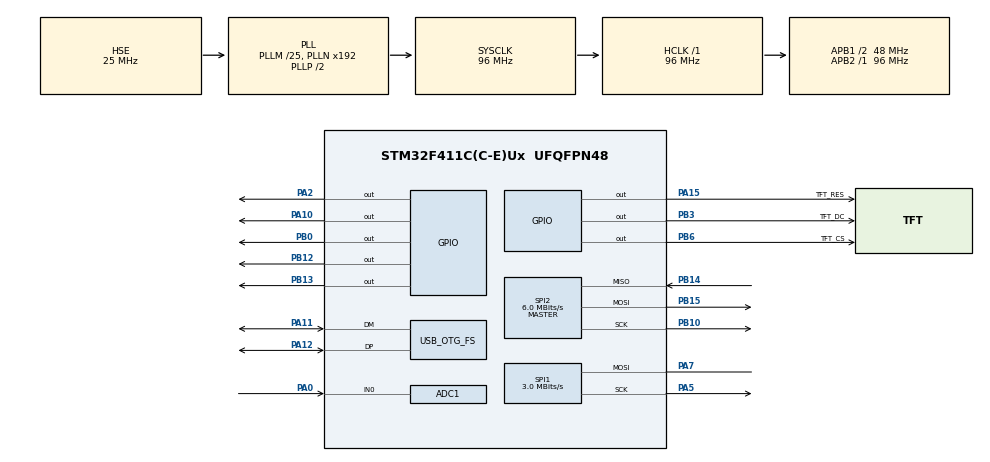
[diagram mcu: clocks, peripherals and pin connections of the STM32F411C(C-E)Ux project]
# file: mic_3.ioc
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ADC1.Channel-2\#ChannelRegularConversion=ADC_CHANNEL_0
ADC1.ClockPrescaler=ADC_CLOCK_SYNC_PCLK_DIV4
ADC1.ExternalTrigConv=ADC_EXTERNALTRIGCONV_T2_TRGO
ADC1.NbrOfConversionFlag=1
ADC1.Rank-2\#ChannelRegularConversion=1
ADC1.SamplingTime-2\#ChannelRegularConversion=ADC_SAMPLETIME_15CYCLES
ADC1.master=1
Dma.ADC1.0.Direction=DMA_PERIPH_TO_MEMORY
Dma.ADC1.0.FIFOMode=DMA_FIFOMODE_DISABLE
Dma.ADC1.0.Instance=DMA2_Stream0
Dma.ADC1.0.MemDataAlignment=DMA_MDATAALIGN_WORD
Dma.ADC1.0.MemInc=DMA_MINC_ENABLE
Dma.ADC1.0.Mode=DMA_CIRCULAR
Dma.ADC1.0.PeriphDataAlignment=DMA_PDATAALIGN_WORD
Dma.ADC1.0.PeriphInc=DMA_PINC_DISABLE
Dma.ADC1.0.Priority=DMA_PRIORITY_LOW
Dma.Request0=ADC1
FATFS._MAX_SS=4096
FATFS._USE_LFN=1
Mcu.Family=STM32F4
Mcu.Name=STM32F411C(C-E)Ux
Mcu.Package=UFQFPN48
NVIC.DMA2_Stream0_IRQn=true\:0\:0\:false\:false\:true\:false\:true\:true
NVIC.OTG_FS_IRQn=true\:0\:0\:false\:false\:true\:false\:true\:true
NVIC.PriorityGroup=NVIC_PRIORITYGROUP_4
PA0-WKUP.Signal=ADCx_IN0
PA10.Signal=GPIO_Output
PA11.Mode=Device_Only
PA11.Signal=USB_OTG_FS_DM
PA12.Mode=Device_Only
PA12.Signal=USB_OTG_FS_DP
PA13.Mode=Serial_Wire
PA13.Signal=SYS_JTMS-SWDIO
PA14.Mode=Serial_Wire
PA14.Signal=SYS_JTCK-SWCLK
PA15.GPIO_Label=TFT_RES
PA15.Signal=GPIO_Output
PA2.Signal=GPIO_Output
PA5.Mode=Simplex_Bidirectional_Master
PA5.Signal=SPI1_SCK
PA7.Mode=Simplex_Bidirectional_Master
PA7.Signal=SPI1_MOSI
PB0.Signal=GPIO_Output
PB10.Mode=Full_Duplex_Master
PB10.Signal=SPI2_SCK
PB12.Signal=GPIO_Output
PB13.Signal=GPIO_Output
PB14.Mode=Full_Duplex_Master
PB14.Signal=SPI2_MISO
PB15.Mode=Full_Duplex_Master
PB15.Signal=SPI2_MOSI
PB3.GPIO_Label=TFT_DC
PB3.Signal=GPIO_Output
PB6.GPIO_Label=TFT_CS
PB6.Signal=GPIO_Output
PH0\ -\ OSC_IN.Mode=HSE-External-Oscillator
PH0\ -\ OSC_IN.Signal=RCC_OSC_IN
PH1\ -\ OSC_OUT.Mode=HSE-External-Oscillator
PH1\ -\ OSC_OUT.Signal=RCC_OSC_OUT
ProjectManager.HeapSize=0x1000
ProjectManager.StackSize=0x400
ProjectManager.TargetToolchain=CMake
RCC.48MHZClocksFreq_Value=48000000
RCC.AHBFreq_Value=96000000
RCC.APB1CLKDivider=RCC_HCLK_DIV2
RCC.APB1Freq_Value=48000000
RCC.APB1TimFreq_Value=96000000
RCC.APB2Freq_Value=96000000
RCC.APB2TimFreq_Value=96000000
RCC.CortexFreq_Value=96000000
RCC.HCLKFreq_Value=96000000
RCC.HSE_VALUE=25000000
RCC.HSI_VALUE=16000000
RCC.LSE_VALUE=32768
RCC.PLLM=25
RCC.SYSCLKFreq_VALUE=96000000
RCC.SYSCLKSource=RCC_SYSCLKSOURCE_PLLCLK
RCC.VCOOutputFreq_Value=192000000
SH.ADCx_IN0.0=ADC1_IN0,IN0
SPI1.BaudRatePrescaler=SPI_BAUDRATEPRESCALER_32
SPI1.CalculateBaudRate=3.0 MBits/s
SPI1.Direction=SPI_DIRECTION_1LINE
SPI1.Mode=SPI_MODE_MASTER
SPI1.VirtualType=VM_MASTER
SPI2.BaudRatePrescaler=SPI_BAUDRATEPRESCALER_8
SPI2.CalculateBaudRate=6.0 MBits/s
SPI2.Direction=SPI_DIRECTION_2LINES
SPI2.Mode=SPI_MODE_MASTER
SPI2.VirtualType=VM_MASTER
TIM2.Period=8000-1
TIM2.Prescaler=1-1
TIM2.TIM_MasterOutputTrigger=TIM_TRGO_UPDATE
TIM2.TIM_MasterSlaveMode=TIM_MASTERSLAVEMODE_ENABLE
USB_DEVICE.CLASS_NAME_FS=CDC
USB_DEVICE.VirtualMode=Cdc
USB_DEVICE.VirtualModeFS=Cdc_FS
USB_OTG_FS.VirtualMode=Device_Only
VP_FATFS_VS_Generic.Mode=User_defined
VP_TIM2_VS_ClockSourceINT.Mode=Internal
VP_USB_DEVICE_VS_USB_DEVICE_CDC_FS.Mode=CDC_FS
board=custom

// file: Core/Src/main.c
/* USER CODE BEGIN Header */
/**
  ******************************************************************************
  * @file           : main.c
  * @brief          : Main program body
  ******************************************************************************
  */
/* USER CODE END Header */
#include "main.h"
#include "fatfs.h"
#include "usb_device.h"

/* USER CODE BEGIN Includes */
#include "app.h"
#include "board.h"
/* USER CODE END Includes */

ADC_HandleTypeDef hadc1;
DMA_HandleTypeDef hdma_adc1;

SPI_HandleTypeDef hspi1;
SPI_HandleTypeDef hspi2;

TIM_HandleTypeDef htim2;

void SystemClock_Config(void);
static void MX_GPIO_Init(void);
static void MX_DMA_Init(void);
static void MX_ADC1_Init(void);
static void MX_TIM2_Init(void);
static void MX_SPI1_Init(void);
static void MX_SPI2_Init(void);

int main(void)
{

  /* MCU Configuration--------------------------------------------------------*/

  /* Reset of all peripherals, Initializes the Flash interface and the Systick. */
  HAL_Init();

  /* Configure the system clock */
  SystemClock_Config();

  /* Initialize all configured peripherals */
  MX_GPIO_Init();
  MX_DMA_Init();
  MX_ADC1_Init();
  MX_USB_DEVICE_Init();
  MX_TIM2_Init();
  MX_SPI1_Init();
  MX_SPI2_Init();
  MX_FATFS_Init();
  /* USER CODE BEGIN 2 */
  App_Init();
  /* USER CODE END 2 */

  /* Infinite loop */
  /* USER CODE BEGIN WHILE */
  while (1)
  {
    App_Run();
    /* USER CODE END WHILE */

  }
}

void SystemClock_Config(void)
{
  RCC_OscInitTypeDef RCC_OscInitStruct = {0};
  RCC_ClkInitTypeDef RCC_ClkInitStruct = {0};

  /** Configure the main internal regulator output voltage
  */
  __HAL_RCC_PWR_CLK_ENABLE();
  __HAL_PWR_VOLTAGESCALING_CONFIG(PWR_REGULATOR_VOLTAGE_SCALE1);

  /** Initializes the RCC Oscillators according to the specified parameters
  * in the RCC_OscInitTypeDef structure.
  */
  RCC_OscInitStruct.OscillatorType = RCC_OSCILLATORTYPE_HSE;
  RCC_OscInitStruct.HSEState = RCC_HSE_ON;
  RCC_OscInitStruct.PLL.PLLState = RCC_PLL_ON;
  RCC_OscInitStruct.PLL.PLLSource = RCC_PLLSOURCE_HSE;
  RCC_OscInitStruct.PLL.PLLM = 25;
  RCC_OscInitStruct.PLL.PLLN = 192;
  RCC_OscInitStruct.PLL.PLLP = RCC_PLLP_DIV2;
  RCC_OscInitStruct.PLL.PLLQ = 4;
  if (HAL_RCC_OscConfig(&RCC_OscInitStruct) != HAL_OK)
  {
    Error_Handler();
  }

  /** Initializes the CPU, AHB and APB buses clocks
  */
  RCC_ClkInitStruct.ClockType = RCC_CLOCKTYPE_HCLK|RCC_CLOCKTYPE_SYSCLK
                              |RCC_CLOCKTYPE_PCLK1|RCC_CLOCKTYPE_PCLK2;
  RCC_ClkInitStruct.SYSCLKSource = RCC_SYSCLKSOURCE_PLLCLK;
  RCC_ClkInitStruct.AHBCLKDivider = RCC_SYSCLK_DIV1;
  RCC_ClkInitStruct.APB1CLKDivider = RCC_HCLK_DIV2;
  RCC_ClkInitStruct.APB2CLKDivider = RCC_HCLK_DIV1;

  if (HAL_RCC_ClockConfig(&RCC_ClkInitStruct, FLASH_LATENCY_3) != HAL_OK)
  {
    Error_Handler();
  }
}

static void MX_ADC1_Init(void)
{

  ADC_ChannelConfTypeDef sConfig = {0};

  /** Configure the global features of the ADC (Clock, Resolution, Data Alignment and number of conversion)
  */
  hadc1.Instance = ADC1;
  hadc1.Init.ClockPrescaler = ADC_CLOCK_SYNC_PCLK_DIV4;
  hadc1.Init.Resolution = ADC_RESOLUTION_12B;
  hadc1.Init.ScanConvMode = DISABLE;
  hadc1.Init.ContinuousConvMode = DISABLE;
  hadc1.Init.DiscontinuousConvMode = DISABLE;
  hadc1.Init.ExternalTrigConvEdge = ADC_EXTERNALTRIGCONVEDGE_RISING;
  hadc1.Init.ExternalTrigConv = ADC_EXTERNALTRIGCONV_T2_TRGO;
  hadc1.Init.DataAlign = ADC_DATAALIGN_RIGHT;
  hadc1.Init.NbrOfConversion = 1;
  hadc1.Init.DMAContinuousRequests = DISABLE;
  hadc1.Init.EOCSelection = ADC_EOC_SINGLE_CONV;
  if (HAL_ADC_Init(&hadc1) != HAL_OK)
  {
    Error_Handler();
  }

  /** Configure for the selected ADC regular channel its corresponding rank in the sequencer and its sample time.
  */
  sConfig.Channel = ADC_CHANNEL_0;
  sConfig.Rank = 1;
  sConfig.SamplingTime = ADC_SAMPLETIME_15CYCLES;
  if (HAL_ADC_ConfigChannel(&hadc1, &sConfig) != HAL_OK)
  {
    Error_Handler();
  }

}

static void MX_SPI1_Init(void)
{

  /* SPI1 parameter configuration*/
  hspi1.Instance = SPI1;
  hspi1.Init.Mode = SPI_MODE_MASTER;
  hspi1.Init.Direction = SPI_DIRECTION_1LINE;
  hspi1.Init.DataSize = SPI_DATASIZE_8BIT;
  hspi1.Init.CLKPolarity = SPI_POLARITY_LOW;
  hspi1.Init.CLKPhase = SPI_PHASE_1EDGE;
  hspi1.Init.NSS = SPI_NSS_SOFT;
  hspi1.Init.BaudRatePrescaler = SPI_BAUDRATEPRESCALER_32;
  hspi1.Init.FirstBit = SPI_FIRSTBIT_MSB;
  hspi1.Init.TIMode = SPI_TIMODE_DISABLE;
  hspi1.Init.CRCCalculation = SPI_CRCCALCULATION_DISABLE;
  hspi1.Init.CRCPolynomial = 10;
  if (HAL_SPI_Init(&hspi1) != HAL_OK)
  {
    Error_Handler();
  }

}

static void MX_SPI2_Init(void)
{

  /* SPI2 parameter configuration*/
  hspi2.Instance = SPI2;
  hspi2.Init.Mode = SPI_MODE_MASTER;
  hspi2.Init.Direction = SPI_DIRECTION_2LINES;
  hspi2.Init.DataSize = SPI_DATASIZE_8BIT;
  hspi2.Init.CLKPolarity = SPI_POLARITY_LOW;
  hspi2.Init.CLKPhase = SPI_PHASE_1EDGE;
  hspi2.Init.NSS = SPI_NSS_SOFT;
  hspi2.Init.BaudRatePrescaler = SPI_BAUDRATEPRESCALER_128;
  hspi2.Init.FirstBit = SPI_FIRSTBIT_MSB;
  hspi2.Init.TIMode = SPI_TIMODE_DISABLE;
  hspi2.Init.CRCCalculation = SPI_CRCCALCULATION_DISABLE;
  hspi2.Init.CRCPolynomial = 10;
  if (HAL_SPI_Init(&hspi2) != HAL_OK)
  {
    Error_Handler();
  }

}

static void MX_TIM2_Init(void)
{

  TIM_ClockConfigTypeDef sClockSourceConfig = {0};
  TIM_MasterConfigTypeDef sMasterConfig = {0};

  htim2.Instance = TIM2;
  htim2.Init.Prescaler = 1-1;
  htim2.Init.CounterMode = TIM_COUNTERMODE_UP;
  htim2.Init.Period = 8000-1;
  htim2.Init.ClockDivision = TIM_CLOCKDIVISION_DIV1;
  htim2.Init.AutoReloadPreload = TIM_AUTORELOAD_PRELOAD_DISABLE;
  if (HAL_TIM_Base_Init(&htim2) != HAL_OK)
  {
    Error_Handler();
  }
  sClockSourceConfig.ClockSource = TIM_CLOCKSOURCE_INTERNAL;
  if (HAL_TIM_ConfigClockSource(&htim2, &sClockSourceConfig) != HAL_OK)
  {
    Error_Handler();
  }
  sMasterConfig.MasterOutputTrigger = TIM_TRGO_UPDATE;
  sMasterConfig.MasterSlaveMode = TIM_MASTERSLAVEMODE_ENABLE;
  if (HAL_TIMEx_MasterConfigSynchronization(&htim2, &sMasterConfig) != HAL_OK)
  {
    Error_Handler();
  }

}

static void MX_DMA_Init(void)
{

  /* DMA controller clock enable */
  __HAL_RCC_DMA2_CLK_ENABLE();

  /* DMA interrupt init */
  /* DMA2_Stream0_IRQn interrupt configuration */
  HAL_NVIC_SetPriority(DMA2_Stream0_IRQn, 0, 0);
  HAL_NVIC_EnableIRQ(DMA2_Stream0_IRQn);

}

static void MX_GPIO_Init(void)
{
  GPIO_InitTypeDef GPIO_InitStruct = {0};

  /* GPIO Ports Clock Enable */
  __HAL_RCC_GPIOH_CLK_ENABLE();
  __HAL_RCC_GPIOA_CLK_ENABLE();
  __HAL_RCC_GPIOB_CLK_ENABLE();

  /*Configure GPIO pin Output Level */
  HAL_GPIO_WritePin(GPIOA, GPIO_PIN_2|GPIO_PIN_10|TFT_RES_Pin, GPIO_PIN_RESET);

  /*Configure GPIO pin Output Level */
  HAL_GPIO_WritePin(GPIOB, GPIO_PIN_0|GPIO_PIN_12|GPIO_PIN_13|TFT_DC_Pin
                          |TFT_CS_Pin, GPIO_PIN_RESET);

  /*Configure GPIO pins : PA2 PA10 TFT_RES_Pin */
  GPIO_InitStruct.Pin = GPIO_PIN_2|GPIO_PIN_10|TFT_RES_Pin;
  GPIO_InitStruct.Mode = GPIO_MODE_OUTPUT_PP;
  GPIO_InitStruct.Pull = GPIO_NOPULL;
  GPIO_InitStruct.Speed = GPIO_SPEED_FREQ_LOW;
  HAL_GPIO_Init(GPIOA, &GPIO_InitStruct);

  /*Configure GPIO pins : PB0 PB12 PB13 TFT_DC_Pin
                           TFT_CS_Pin */
  GPIO_InitStruct.Pin = GPIO_PIN_0|GPIO_PIN_12|GPIO_PIN_13|TFT_DC_Pin
                          |TFT_CS_Pin;
  GPIO_InitStruct.Mode = GPIO_MODE_OUTPUT_PP;
  GPIO_InitStruct.Pull = GPIO_NOPULL;
  GPIO_InitStruct.Speed = GPIO_SPEED_FREQ_LOW;
  HAL_GPIO_Init(GPIOB, &GPIO_InitStruct);

  /*Configure GPIO pin : BTN_OK_Pin */
  GPIO_InitStruct.Pin = BTN_OK_Pin;
  GPIO_InitStruct.Mode = GPIO_MODE_INPUT;
  GPIO_InitStruct.Pull = GPIO_PULLUP;
  GPIO_InitStruct.Speed = GPIO_SPEED_FREQ_LOW;
  HAL_GPIO_Init(BTN_OK_GPIO_Port, &GPIO_InitStruct);

  /*Configure GPIO pin : BTN_NAV_Pin */
  GPIO_InitStruct.Pin = BTN_NAV_Pin;
  GPIO_InitStruct.Mode = GPIO_MODE_INPUT;
  GPIO_InitStruct.Pull = GPIO_PULLUP;
  HAL_GPIO_Init(BTN_NAV_GPIO_Port, &GPIO_InitStruct);

}

void Error_Handler(void)
{
  __disable_irq();
  while (1)
  {
  }
}
